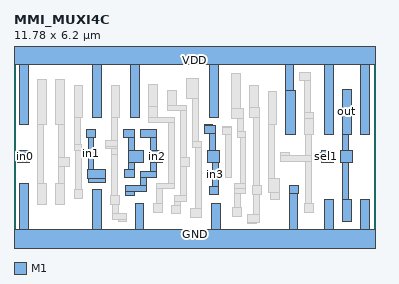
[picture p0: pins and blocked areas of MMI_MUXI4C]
MACRO MMI_MUXI4C
	CLASS CORE ;
	FOREIGN MMI_MUXI4C 0 0 ;
	SIZE 11.78 BY 6.2 ;
	SYMMETRY X Y ;
	SITE CORE1 ;
	PIN out
		DIRECTION output ;
		USE SIGNAL ;
		PORT
			LAYER M1 ;
			RECT 10.72 3.515 11 4.985 ;
			LAYER M1 ;
			RECT 10.725 2.98 10.92 3.515 ;
			LAYER M1 ;
			RECT 10.665 2.6 11.04 2.98 ;
			LAYER M1 ;
			RECT 10.725 1.375 10.92 2.6 ;
			LAYER M1 ;
			RECT 10.72 0.675 11 1.375 ;
		END
		AntennaDiffArea 1.0164 ;
	END out
	PIN in1
		DIRECTION input ;
		USE SIGNAL ;
		PORT
			LAYER M1 ;
			RECT 2.365 3.405 2.645 3.685 ;
			LAYER M1 ;
			RECT 2.415 2.36 2.61 3.405 ;
			LAYER M1 ;
			RECT 2.4 2.08 2.98 2.36 ;
			LAYER M1 ;
			RECT 2.415 1.955 2.98 2.08 ;
		END
		AntennaGateArea 0.3465 ;
	END in1
	PIN sel0
		DIRECTION input ;
		USE SIGNAL ;
		PORT
			LAYER M1 ;
			RECT 3.57 3.68 3.85 3.685 ;
			LAYER M1 ;
			RECT 3.57 3.405 3.925 3.68 ;
			LAYER M1 ;
			RECT 3.735 2.98 3.925 3.405 ;
			LAYER M1 ;
			RECT 3.735 2.6 4.22 2.98 ;
			LAYER M1 ;
			RECT 3.735 2.375 3.925 2.6 ;
			LAYER M1 ;
			RECT 3.6 2.11 3.925 2.375 ;
			LAYER M1 ;
			RECT 3.6 2.095 3.88 2.11 ;
		END
		AntennaGateArea 1.0395 ;
	END sel0
	PIN GND
		DIRECTION inout ;
		USE GROUND ;
		PORT
			LAYER M1 ;
			RECT 0.185 0.42 0.465 1.925 ;
			LAYER M1 ;
			RECT 8.995 1.855 9.275 1.86 ;
			LAYER M1 ;
			RECT 2.565 0.42 2.845 1.705 ;
			LAYER M1 ;
			RECT 8.98 1.58 9.275 1.855 ;
			LAYER M1 ;
			RECT 3.95 0.42 4.23 1.27 ;
			LAYER M1 ;
			RECT 6.455 0.42 6.735 1.265 ;
			LAYER M1 ;
			RECT 8.98 0.42 9.265 1.58 ;
			LAYER M1 ;
			RECT 10.13 0.42 10.41 1.375 ;
			LAYER M1 ;
			RECT 11.31 0.42 11.59 1.375 ;
			LAYER M1 ;
			RECT 0 -0.42 11.78 0.42 ;
		END
	END GND
	PIN in2
		DIRECTION input ;
		USE SIGNAL ;
		PORT
			LAYER M1 ;
			RECT 4.14 3.405 4.655 3.685 ;
			LAYER M1 ;
			RECT 4.46 2.98 4.655 3.405 ;
			LAYER M1 ;
			RECT 4.46 2.6 4.84 2.98 ;
			LAYER M1 ;
			RECT 4.46 2.315 4.655 2.6 ;
			LAYER M1 ;
			RECT 4.125 2.12 4.655 2.315 ;
			LAYER M1 ;
			RECT 4.125 1.835 4.315 2.12 ;
			LAYER M1 ;
			RECT 3.645 1.64 4.315 1.835 ;
			LAYER M1 ;
			RECT 3.645 1.525 3.925 1.64 ;
		END
		AntennaGateArea 0.34425 ;
	END in2
	PIN sel1
		DIRECTION input ;
		USE SIGNAL ;
		PORT
			LAYER M1 ;
			RECT 10.045 2.93 10.42 2.98 ;
			LAYER M1 ;
			RECT 9.945 2.65 10.42 2.93 ;
			LAYER M1 ;
			RECT 10.045 2.6 10.42 2.65 ;
		END
		AntennaGateArea 0.51975 ;
	END sel1
	PIN VDD
		DIRECTION inout ;
		USE POWER ;
		PORT
			LAYER M1 ;
			RECT 0 5.78 11.78 6.62 ;
			LAYER M1 ;
			RECT 0.185 3.84 0.465 5.78 ;
			LAYER M1 ;
			RECT 2.565 4.055 2.845 5.78 ;
			LAYER M1 ;
			RECT 3.805 4.07 4.085 5.78 ;
			LAYER M1 ;
			RECT 6.38 4.055 6.66 5.78 ;
			LAYER M1 ;
			RECT 8.85 4.945 9.11 5.78 ;
			LAYER M1 ;
			RECT 8.85 3.5 9.175 4.945 ;
			LAYER M1 ;
			RECT 10.13 3.515 10.41 5.78 ;
			LAYER M1 ;
			RECT 11.31 3.515 11.59 5.78 ;
			LAYER M1 ;
			RECT 8.895 3.495 9.175 3.5 ;
		END
	END VDD
	PIN in3
		DIRECTION input ;
		USE SIGNAL ;
		PORT
			LAYER M1 ;
			RECT 6.21 3.815 6.49 3.83 ;
			LAYER M1 ;
			RECT 6.21 3.55 6.585 3.815 ;
			LAYER M1 ;
			RECT 6.395 2.98 6.585 3.55 ;
			LAYER M1 ;
			RECT 6.32 2.6 6.7 2.98 ;
			LAYER M1 ;
			RECT 6.48 1.82 6.67 2.6 ;
			LAYER M1 ;
			RECT 6.375 1.555 6.67 1.82 ;
			LAYER M1 ;
			RECT 6.375 1.54 6.655 1.555 ;
		END
		AntennaGateArea 0.3465 ;
	END in3
	PIN in0
		DIRECTION input ;
		USE SIGNAL ;
		PORT
			LAYER M1 ;
			RECT 0.12 2.935 0.5 2.98 ;
			LAYER M1 ;
			RECT 0.12 2.655 0.54 2.935 ;
			LAYER M1 ;
			RECT 0.12 2.6 0.5 2.655 ;
		END
		AntennaGateArea 0.3465 ;
	END in0
	OBS
		LAYER M1 ;
		RECT 0.775 3.84 1.055 5.31 ;
		LAYER M1 ;
		RECT 1.365 3.84 1.645 5.31 ;
		LAYER M1 ;
		RECT 1.965 4.055 2.245 5.115 ;
		LAYER M1 ;
		RECT 3.18 5.115 3.37 5.12 ;
		LAYER M1 ;
		RECT 3.17 4.055 3.45 5.115 ;
		LAYER M1 ;
		RECT 5.615 5.325 5.895 5.34 ;
		LAYER M1 ;
		RECT 4.405 4.42 4.685 5.135 ;
		LAYER M1 ;
		RECT 5.01 4.47 5.29 4.95 ;
		LAYER M1 ;
		RECT 5.615 4.67 6.01 5.325 ;
		LAYER M1 ;
		RECT 4.405 4.075 4.69 4.42 ;
		LAYER M1 ;
		RECT 5.005 4.28 5.62 4.47 ;
		LAYER M1 ;
		RECT 0.775 1.925 0.965 3.84 ;
		LAYER M1 ;
		RECT 1.45 2.745 1.64 3.84 ;
		LAYER M1 ;
		RECT 1.97 3.195 2.165 4.055 ;
		LAYER M1 ;
		RECT 1.97 3 2.2 3.195 ;
		LAYER M1 ;
		RECT 1.45 2.465 1.81 2.745 ;
		LAYER M1 ;
		RECT 1.45 1.925 1.64 2.465 ;
		LAYER M1 ;
		RECT 0.775 1.225 1.055 1.925 ;
		LAYER M1 ;
		RECT 1.365 1.225 1.645 1.925 ;
		LAYER M1 ;
		RECT 2.01 1.705 2.2 3 ;
		LAYER M1 ;
		RECT 3.18 3.315 3.37 4.055 ;
		LAYER M1 ;
		RECT 4.405 3.885 5.23 4.075 ;
		LAYER M1 ;
		RECT 2.995 3.105 3.37 3.315 ;
		LAYER M1 ;
		RECT 2.995 3.035 3.375 3.105 ;
		LAYER M1 ;
		RECT 3.18 2.87 3.375 3.035 ;
		LAYER M1 ;
		RECT 1.965 1.425 2.245 1.705 ;
		LAYER M1 ;
		RECT 3.185 1.505 3.375 2.87 ;
		LAYER M1 ;
		RECT 5.04 1.92 5.23 3.885 ;
		LAYER M1 ;
		RECT 4.645 1.73 5.23 1.92 ;
		LAYER M1 ;
		RECT 5.43 2.755 5.62 4.28 ;
		LAYER M1 ;
		RECT 5.82 3.29 6.01 4.67 ;
		LAYER M1 ;
		RECT 7.1 4.35 7.38 5.49 ;
		LAYER M1 ;
		RECT 7.695 4.395 7.975 5.115 ;
		LAYER M1 ;
		RECT 9.485 5.535 9.68 5.545 ;
		LAYER M1 ;
		RECT 9.32 5.255 9.68 5.535 ;
		LAYER M1 ;
		RECT 7.1 4.02 7.495 4.35 ;
		LAYER M1 ;
		RECT 7.695 4.055 8.01 4.395 ;
		LAYER M1 ;
		RECT 5.82 3.095 6.12 3.29 ;
		LAYER M1 ;
		RECT 5.43 2.475 5.73 2.755 ;
		LAYER M1 ;
		RECT 3.165 1.225 3.445 1.505 ;
		LAYER M1 ;
		RECT 3.205 0.945 3.395 1.225 ;
		LAYER M1 ;
		RECT 3.205 0.94 3.615 0.945 ;
		LAYER M1 ;
		RECT 3.205 0.75 3.675 0.94 ;
		LAYER M1 ;
		RECT 3.395 0.66 3.675 0.75 ;
		LAYER M1 ;
		RECT 4.645 1.25 4.835 1.73 ;
		LAYER M1 ;
		RECT 5.43 1.53 5.62 2.475 ;
		LAYER M1 ;
		RECT 4.555 0.97 4.835 1.25 ;
		LAYER M1 ;
		RECT 5.245 1.335 5.62 1.53 ;
		LAYER M1 ;
		RECT 5.245 1.205 5.435 1.335 ;
		LAYER M1 ;
		RECT 5.155 0.925 5.435 1.205 ;
		LAYER M1 ;
		RECT 5.93 1.08 6.12 3.095 ;
		LAYER M1 ;
		RECT 6.815 3.735 7.095 3.775 ;
		LAYER M1 ;
		RECT 6.815 3.495 7.105 3.735 ;
		LAYER M1 ;
		RECT 6.915 2.105 7.105 3.495 ;
		LAYER M1 ;
		RECT 7.305 3.61 7.495 4.02 ;
		LAYER M1 ;
		RECT 7.305 3.4 7.57 3.61 ;
		LAYER M1 ;
		RECT 7.38 1.905 7.57 3.4 ;
		LAYER M1 ;
		RECT 7.185 1.76 7.57 1.905 ;
		LAYER M1 ;
		RECT 7.815 1.84 8.01 4.055 ;
		LAYER M1 ;
		RECT 8.3 3.84 8.58 4.9 ;
		LAYER M1 ;
		RECT 8.305 2.075 8.495 3.84 ;
		LAYER M1 ;
		RECT 9.485 4.215 9.68 5.255 ;
		LAYER M1 ;
		RECT 9.485 4.02 9.775 4.215 ;
		LAYER M1 ;
		RECT 9.495 3.515 9.775 4.02 ;
		LAYER M1 ;
		RECT 8.695 2.825 8.975 2.915 ;
		LAYER M1 ;
		RECT 9.505 2.825 9.695 3.515 ;
		LAYER M1 ;
		RECT 8.695 2.635 9.695 2.825 ;
		LAYER M1 ;
		RECT 8.715 2.63 9.695 2.635 ;
		LAYER M1 ;
		RECT 7.18 1.57 7.57 1.76 ;
		LAYER M1 ;
		RECT 5.76 0.8 6.12 1.08 ;
		LAYER M1 ;
		RECT 7.18 1.11 7.375 1.57 ;
		LAYER M1 ;
		RECT 7.785 1.56 8.065 1.84 ;
		LAYER M1 ;
		RECT 8.305 1.6 8.665 2.075 ;
		LAYER M1 ;
		RECT 7.14 0.83 7.42 1.11 ;
		LAYER M1 ;
		RECT 7.815 0.9 8.01 1.56 ;
		LAYER M1 ;
		RECT 8.385 1.375 8.665 1.6 ;
		LAYER M1 ;
		RECT 7.62 0.625 8.01 0.9 ;
		LAYER M1 ;
		RECT 7.62 0.62 7.9 0.625 ;
		LAYER M1 ;
		RECT 9.505 1.27 9.695 2.63 ;
		LAYER M1 ;
		RECT 9.495 0.955 9.775 1.27 ;
	END
END MMI_MUXI4C
